###############################################################
#  Generated by:      Cadence Innovus 21.15-s110_1
#  OS:                Linux x86_64(Host ID ra01)
#  Generated on:      Thu Jan 22 17:28:46 2026
#  Design:            counter
#  Command:           write_lef_abstract counter.lef
###############################################################

VERSION 5.8 ;

BUSBITCHARS "[]" ;
DIVIDERCHAR "/" ;

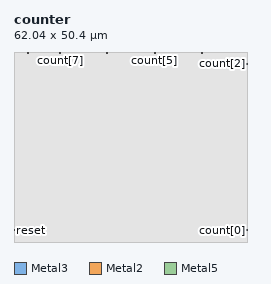
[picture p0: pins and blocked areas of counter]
MACRO counter
  CLASS BLOCK ;
  SIZE 62.040000 BY 50.400000 ;
  FOREIGN counter 0.000000 0.000000 ;
  ORIGIN 0 0 ;
  SYMMETRY X Y R90 ;
  PIN reset
    DIRECTION INPUT ;
    USE SIGNAL ;
    ANTENNAPARTIALMETALAREA 3.024 LAYER Metal3  ;
    ANTENNAPARTIALMETALSIDEAREA 11.448 LAYER Metal3  ;
    ANTENNAMODEL OXIDE1 ;
    ANTENNAGATEAREA 0.6696 LAYER Metal3  ;
    ANTENNAMAXAREACAR 10.7322 LAYER Metal3  ;
    ANTENNAMAXSIDEAREACAR 41.1272 LAYER Metal3  ;
    ANTENNAMAXCUTCAR 0.403823 LAYER Via34  ;
    PORT
      LAYER Metal3 ;
        RECT 0.000000 2.940000 0.280000 3.220000 ;
    END
  END reset
  PIN clk
    DIRECTION INPUT ;
    USE SIGNAL ;
    ANTENNAPARTIALMETALAREA 11.9564 LAYER Metal2  ;
    ANTENNAPARTIALMETALSIDEAREA 45.1666 LAYER Metal2  ;
    ANTENNAMODEL OXIDE1 ;
    ANTENNAGATEAREA 0.4824 LAYER Metal2  ;
    ANTENNAMAXAREACAR 34.2522 LAYER Metal2  ;
    ANTENNAMAXSIDEAREACAR 135.999 LAYER Metal2  ;
    ANTENNAMAXCUTCAR 1.50222 LAYER Via23  ;
    PORT
      LAYER Metal2 ;
        RECT 3.490000 50.120000 3.770000 50.400000 ;
    END
  END clk
  PIN count[7]
    DIRECTION OUTPUT ;
    USE SIGNAL ;
    ANTENNADIFFAREA 0.56 LAYER Metal2  ;
    ANTENNAPARTIALMETALAREA 3.346 LAYER Metal2  ;
    ANTENNAPARTIALMETALSIDEAREA 12.667 LAYER Metal2  ;
    PORT
      LAYER Metal2 ;
        RECT 12.070000 50.120000 12.350000 50.400000 ;
    END
  END count[7]
  PIN count[6]
    DIRECTION OUTPUT ;
    USE SIGNAL ;
    ANTENNAPARTIALMETALAREA 4.942 LAYER Metal2  ;
    ANTENNAPARTIALMETALSIDEAREA 18.709 LAYER Metal2  ;
    ANTENNAPARTIALCUTAREA 0.1352 LAYER Via23  ;
    ANTENNADIFFAREA 0.72 LAYER Metal3  ;
    ANTENNAPARTIALMETALAREA 2.4376 LAYER Metal3  ;
    ANTENNAPARTIALMETALSIDEAREA 9.328 LAYER Metal3  ;
    ANTENNAMODEL OXIDE1 ;
    ANTENNAGATEAREA 0.3924 LAYER Metal3  ;
    ANTENNAMAXAREACAR 15.0626 LAYER Metal3  ;
    ANTENNAMAXSIDEAREACAR 57.4766 LAYER Metal3  ;
    ANTENNAMAXCUTCAR 1.74677 LAYER Via34  ;
    PORT
      LAYER Metal2 ;
        RECT 24.610000 50.120000 24.890000 50.400000 ;
    END
  END count[6]
  PIN count[5]
    DIRECTION OUTPUT ;
    USE SIGNAL ;
    ANTENNAPARTIALMETALAREA 6.659 LAYER Metal2  ;
    ANTENNAPARTIALMETALSIDEAREA 24.592 LAYER Metal2  ;
    ANTENNAMODEL OXIDE1 ;
    ANTENNAGATEAREA 0.3924 LAYER Metal2  ;
    ANTENNAMAXAREACAR 24.4111 LAYER Metal2  ;
    ANTENNAMAXSIDEAREACAR 96.4976 LAYER Metal2  ;
    ANTENNAPARTIALCUTAREA 0.1352 LAYER Via23  ;
    ANTENNAMAXCUTCAR 1.21793 LAYER Via23  ;
    ANTENNADIFFAREA 0.72 LAYER Metal3  ;
    ANTENNAPARTIALMETALAREA 2.8784 LAYER Metal3  ;
    ANTENNAPARTIALMETALSIDEAREA 11.1936 LAYER Metal3  ;
    ANTENNAGATEAREA 0.3924 LAYER Metal3  ;
    ANTENNAMAXAREACAR 31.7465 LAYER Metal3  ;
    ANTENNAMAXSIDEAREACAR 125.024 LAYER Metal3  ;
    ANTENNAMAXCUTCAR 1.21793 LAYER Via34  ;
    PORT
      LAYER Metal2 ;
        RECT 37.150000 50.120000 37.430000 50.400000 ;
    END
  END count[5]
  PIN count[4]
    DIRECTION OUTPUT ;
    USE SIGNAL ;
    ANTENNADIFFAREA 0.72 LAYER Metal2  ;
    ANTENNAPARTIALMETALAREA 6.9612 LAYER Metal2  ;
    ANTENNAPARTIALMETALSIDEAREA 25.9594 LAYER Metal2  ;
    ANTENNAMODEL OXIDE1 ;
    ANTENNAGATEAREA 0.3924 LAYER Metal2  ;
    ANTENNAMAXAREACAR 23.3686 LAYER Metal2  ;
    ANTENNAMAXSIDEAREACAR 91.6283 LAYER Metal2  ;
    ANTENNAMAXCUTCAR 0.873385 LAYER Via23  ;
    PORT
      LAYER Metal2 ;
        RECT 49.690000 50.120000 49.970000 50.400000 ;
    END
  END count[4]
  PIN count[3]
    DIRECTION OUTPUT ;
    USE SIGNAL ;
    ANTENNADIFFAREA 0.72 LAYER Metal3  ;
    ANTENNAPARTIALMETALAREA 4.7544 LAYER Metal3  ;
    ANTENNAPARTIALMETALSIDEAREA 18.2956 LAYER Metal3  ;
    ANTENNAMODEL OXIDE1 ;
    ANTENNAGATEAREA 0.3924 LAYER Metal3  ;
    ANTENNAMAXAREACAR 49.5253 LAYER Metal3  ;
    ANTENNAMAXSIDEAREACAR 189.297 LAYER Metal3  ;
    ANTENNAMAXCUTCAR 1.70707 LAYER Via34  ;
    PORT
      LAYER Metal3 ;
        RECT 61.760000 47.180000 62.040000 47.460000 ;
    END
  END count[3]
  PIN count[2]
    DIRECTION OUTPUT ;
    USE SIGNAL ;
    ANTENNADIFFAREA 0.72 LAYER Metal5  ;
    ANTENNAPARTIALMETALAREA 0.4368 LAYER Metal5  ;
    ANTENNAPARTIALMETALSIDEAREA 1.6536 LAYER Metal5  ;
    ANTENNAMODEL OXIDE1 ;
    ANTENNAGATEAREA 0.3924 LAYER Metal5  ;
    ANTENNAMAXAREACAR 45.1987 LAYER Metal5  ;
    ANTENNAMAXSIDEAREACAR 175.504 LAYER Metal5  ;
    ANTENNAMAXCUTCAR 1.90702 LAYER Via56  ;
    PORT
      LAYER Metal5 ;
        RECT 61.760000 47.180000 62.040000 47.460000 ;
    END
  END count[2]
  PIN count[1]
    DIRECTION OUTPUT ;
    USE SIGNAL ;
    ANTENNADIFFAREA 0.72 LAYER Metal3  ;
    ANTENNAPARTIALMETALAREA 9.1896 LAYER Metal3  ;
    ANTENNAPARTIALMETALSIDEAREA 35.086 LAYER Metal3  ;
    ANTENNAMODEL OXIDE1 ;
    ANTENNAGATEAREA 0.2376 LAYER Metal3  ;
    ANTENNAMAXAREACAR 55.2685 LAYER Metal3  ;
    ANTENNAMAXSIDEAREACAR 210.439 LAYER Metal3  ;
    ANTENNAMAXCUTCAR 1.70707 LAYER Via34  ;
    PORT
      LAYER Metal3 ;
        RECT 61.760000 2.940000 62.040000 3.220000 ;
    END
  END count[1]
  PIN count[0]
    DIRECTION OUTPUT ;
    USE SIGNAL ;
    ANTENNADIFFAREA 0.72 LAYER Metal5  ;
    ANTENNAPARTIALMETALAREA 0.4368 LAYER Metal5  ;
    ANTENNAPARTIALMETALSIDEAREA 1.6536 LAYER Metal5  ;
    ANTENNAMODEL OXIDE1 ;
    ANTENNAGATEAREA 0.4968 LAYER Metal5  ;
    ANTENNAMAXAREACAR 43.3305 LAYER Metal5  ;
    ANTENNAMAXSIDEAREACAR 165.589 LAYER Metal5  ;
    ANTENNAMAXCUTCAR 1.68233 LAYER Via56  ;
    PORT
      LAYER Metal5 ;
        RECT 61.760000 2.940000 62.040000 3.220000 ;
    END
  END count[0]
  OBS
    LAYER Metal1 ;
      RECT 0.000000 0.000000 62.040000 50.400000 ;
    LAYER Metal2 ;
      RECT 50.250000 49.840000 62.040000 50.400000 ;
      RECT 37.710000 49.840000 49.410000 50.400000 ;
      RECT 25.170000 49.840000 36.870000 50.400000 ;
      RECT 12.630000 49.840000 24.330000 50.400000 ;
      RECT 4.050000 49.840000 11.790000 50.400000 ;
      RECT 0.000000 49.840000 3.210000 50.400000 ;
      RECT 0.000000 0.000000 62.040000 49.840000 ;
    LAYER Metal3 ;
      RECT 0.000000 47.740000 62.040000 50.400000 ;
      RECT 0.000000 46.900000 61.480000 47.740000 ;
      RECT 0.000000 3.500000 62.040000 46.900000 ;
      RECT 0.560000 2.660000 61.480000 3.500000 ;
      RECT 0.000000 0.000000 62.040000 2.660000 ;
    LAYER Metal4 ;
      RECT 0.000000 0.000000 62.040000 50.400000 ;
    LAYER Metal5 ;
      RECT 0.000000 47.740000 62.040000 50.400000 ;
      RECT 0.000000 46.900000 61.480000 47.740000 ;
      RECT 0.000000 3.500000 62.040000 46.900000 ;
      RECT 0.000000 2.660000 61.480000 3.500000 ;
      RECT 0.000000 0.000000 62.040000 2.660000 ;
    LAYER Metal6 ;
      RECT 0.000000 0.000000 62.040000 50.400000 ;
  END
END counter

END LIBRARY
